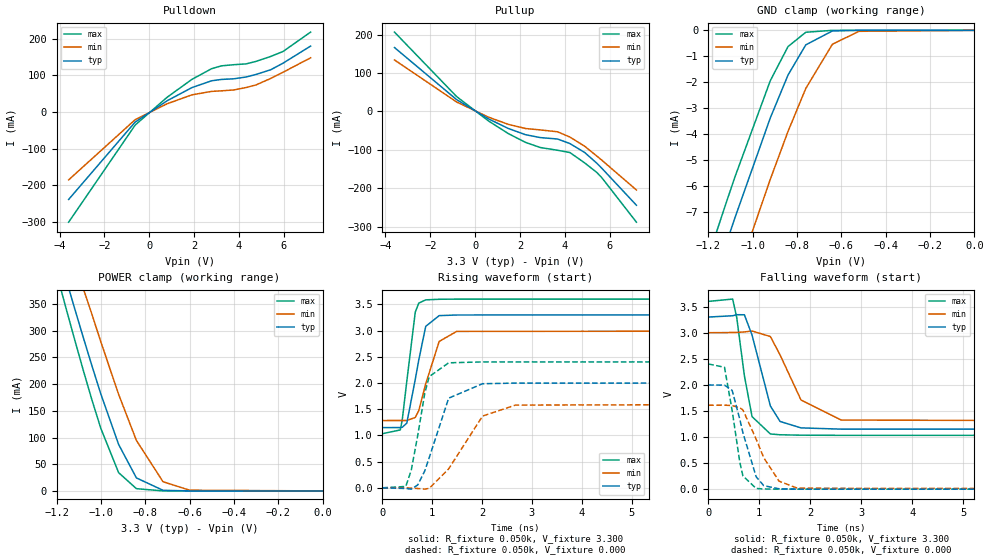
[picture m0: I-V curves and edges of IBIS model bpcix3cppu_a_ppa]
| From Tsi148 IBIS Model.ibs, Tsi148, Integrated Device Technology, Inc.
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|   MODEL bpcix3cppu_a_ppa
[Model]   bpcix3cppu_a_ppa
Model_type   I/O
Vinl  = 0.8V
Vinh  = 2.0V
Vref  = 0.0V
Rref  = 1k
Cref  = 10pF
Vmeas = 1.4V
| Values for delay from A to PAD (Tdo) are determined using
| Vref, Cref, Rref, and Vmeas.
|   INPUT TRANSITION ON DRIVER INPUT = 0.1ns
|   typ   min   max
| Tdo (rise)   1.34n   0.92n   2.02n
| Tdo (fall)   1.41n   1.01n   2.06n
|   INPUT TRANSITION ON DRIVER INPUT = 1.0ns
|   typ   min   max
| Tdo (rise)   1.37n   0.91n   2.08n
| Tdo (fall)   1.56n   1.16n   2.22n
|   typ   min   max
C_comp   2.58pF   2.53pF  2.63pF
[Temperature Range]   50.00   125.00   0.00
[Voltage Range]   3.300   3.000   3.600
|   typ   min   max
|[Supply]   VDD   1.80   1.65   1.95
|[Supply]   VDD330   3.30   3.00   3.60
[Add Submodel]
| Submodel Name   Mode
Up.bpcix3cppu_a.ppa   Non-Driving
Dn.bpcix3cppu_a.ppa   Non-Driving
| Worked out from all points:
|   slope of the pulldown table from 0 to 0.495 V, typ, clamps not added: 25.5 ohm
|   slope of the pullup table from 0 to 0.495 V, typ, clamps not added: 30.3 ohm
|   GND clamp passes 1 mA (typ) near -0.80 V on its own axis
|   POWER clamp passes 1 mA (typ) near -0.71 V on its own axis
|   rising waveform, R_fixture 0.050k, V_fixture 3.300: 20-80 % time 240ps typ, 295ps min, 185ps max; typ from 1.15 V to 3.3 V
|   falling waveform, R_fixture 0.050k, V_fixture 3.300: 20-80 % time 345ps typ, 534ps min, 232ps max; typ from 3.3 V to 1.15 V
|   rising waveform, R_fixture 0.050k, V_fixture 0.000: 20-80 % time 394ps typ, 626ps min, 264ps max; typ from 0 V to 2 V
|   falling waveform, R_fixture 0.050k, V_fixture 0.000: 20-80 % time 317ps typ, 434ps min, 221ps max; typ from 2 V to 0 V
[Pullup]   | Note: Vtable = Vcc - Vout
| Voltage   I(typ)   I(min)   I(max)
-3.6V     166.1mA    133.8mA    206.3mA
-830mV    30.72mA    24.48mA    38.72mA
600mV     -19.63mA   -15.18mA   -25.14mA
1.48V     -44.54mA   -33.84mA   -57.85mA
2.25V     -60.8mA    -44.7mA    -80.81mA
2.91V     -68.31mA   -48.31mA   -94.15mA
3.68V     -72mA      -53.25mA   -101.3mA
4.23V     -83.85mA   -66.9mA    -107.2mA
4.89V     -107.1mA   -90.82mA   -134.2mA
5.44V     -135.4mA   -116.7mA   -159.5mA
5.66V     -148.5mA   -127.4mA   -173.1mA
7.2V      -244.4mA   -204.7mA   -288.5mA
[Pulldown]   | Note: Vtable = Vout
| Voltage   I(typ)   I(min)   I(max)
-3.6V     -238.4mA   -185mA     -300.3mA
-630mV    -27.45mA   -20.86mA   -35.6mA
800mV     30.77mA    22.49mA    40.33mA
1.9V      66.46mA    46.73mA    88.87mA
2.78V     85.09mA    56.17mA    118mA
3.22V     88.75mA    57.7mA     125.8mA
3.77V     90.48mA    60.08mA    128.9mA
4.32V     95.42mA    66.66mA    131.1mA
4.76V     102.3mA    73.69mA    137.9mA
5.42V     115.2mA    91.42mA    151.4mA
5.97V     133.1mA    108.4mA    165mA
7.2V      179.7mA    147.7mA    217.8mA
[POWER_Clamp]   | Note: Vtable = Vcc - Vout
| Voltage   I(typ)   I(min)   I(max)
-3.6V     3.946A     3.816A     4.188A
-1.2V     455.7mA    530.2mA    407.9mA
-1.16V    400.6mA    479.4mA    346.3mA
-1.12V    343.9mA    429.2mA    285.8mA
-1.08V    288.1mA    379.7mA    226.7mA
-1.04V    233.7mA    330.1mA    169.8mA
-1V       181.1mA    278.8mA    116.7mA
-920mV    86.97mA    180.7mA    34.22mA
-840mV    24.39mA    94.6mA     4.235mA
-720mV    1.176mA    17.25mA    44uA
-600mV    19uA       1.348mA    0A
0V        0A         0A         0A
[GND_Clamp]   | Note: Vtable = Vout
| Voltage   I(typ)   I(min)   I(max)
-3.6V     -76.49mA   -78.79mA   -75.06mA
-1.28V    -12.45mA   -14.94mA   -10.87mA
-1.24V    -11.4mA    -13.88mA   -9.809mA
-1.2V     -10.35mA   -12.84mA   -8.759mA
-1.12V    -8.273mA   -10.76mA   -6.689mA
-1.08V    -7.253mA   -9.729mA   -5.675mA
-920mV    -3.381mA   -5.752mA   -1.944mA
-840mV    -1.725mA   -3.901mA   -626uA
-760mV    -561uA     -2.244mA   -74uA
-640mV    -23uA      -536uA     -1uA
-520mV    0A         -38uA      0A
0V        0A         0A         0A
[Ramp]
| variable   typ   min   max
  dV/dt_r   1.20/0.40n   0.97/0.64n   1.44/0.27n
  dV/dt_f   1.29/0.34n   1.03/0.53n   1.54/0.23n
R_load = 0.05k
[Rising Waveform]
R_fixture = 0.050k
V_fixture = 3.300
V_fixture_min = 3.000
V_fixture_max = 3.600
|   time   V(typ)   V(min)   V(max)
0s        1.148V     1.283V     1.032V
360ps     1.149V     1.284V     1.104V
400ps     1.155V     1.284V     1.302V
490ps     1.233V     1.284V     2.029V
660ps     2.066V     1.342V     3.35V
730ps     2.435V     1.47V      3.522V
870ps     3.08V      1.983V     3.585V
1.14ns    3.284V     2.792V     3.596V
1.49ns    3.296V     2.983V     3.599V
19.9ns    3.3V       3V         3.6V
[Falling Waveform]
R_fixture = 0.050k
V_fixture = 3.300
V_fixture_min = 3.000
V_fixture_max = 3.600
|   time   V(typ)   V(min)   V(max)
0s        3.3V       3V         3.6V
480ps     3.325V     3.004V     3.645V
560ps     3.345V     3.006V     3.289V
710ps     3.344V     3.014V     2.174V
860ps     2.954V     3.033V     1.391V
1.22ns    1.594V     2.926V     1.058V
1.41ns    1.298V     2.573V     1.043V
1.82ns    1.175V     1.71V      1.035V
2.61ns    1.151V     1.325V     1.032V
19.9ns    1.148V     1.283V     1.032V
[Rising Waveform]
R_fixture = 0.050k
V_fixture = 0.000
V_fixture_min = 0.000
V_fixture_max = 0.000
|   time   V(typ)   V(min)   V(max)
0s        0V         0V         0V
470ps     -13mV      -1mV       26mV
580ps     -26mV      -6mV       336mV
710ps     55mV       -14mV      1.002V
850ps     321mV      -25mV      1.802V
940ps     574mV      -10mV      2.121V
1.33ns    1.71V      361mV      2.384V
2.01ns    1.985V     1.368V     2.401V
2.67ns    1.997V     1.578V     2.401V
19.9ns    1.998V     1.609V     2.401V
[Falling Waveform]
R_fixture = 0.050k
V_fixture = 0.000
V_fixture_min = 0.000
V_fixture_max = 0.000
|   time   V(typ)   V(min)   V(max)
0s        1.998V     1.609V     2.401V
320ps     1.994V     1.611V     2.337V
470ps     1.894V     1.603V     1.506V
620ps     1.339V     1.56V      518mV
680ps     1.085V     1.52V      256mV
940ps     238mV      961mV      14mV
1.09ns    67mV       602mV      4mV
1.39ns    7mV        153mV      1mV
1.75ns    1mV        18mV       0V
19.9ns    0V         0V         0V
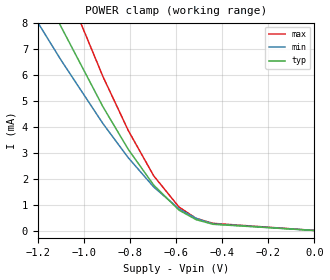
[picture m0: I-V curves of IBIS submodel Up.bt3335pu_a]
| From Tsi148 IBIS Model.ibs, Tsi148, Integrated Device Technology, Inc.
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[Submodel]  Up.bt3335pu_a
Submodel_type   Dynamic_clamp
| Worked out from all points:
|   POWER clamp passes 1 mA (typ) near -0.62 V on its own axis
[POWER Clamp]   | Note: Vtable = Vcc - Vout
| Voltage   I(typ)   I(min)   I(max)
-3.6V     60.61mA    47.86mA    76.15mA
-1.32V    11.99mA    9.826mA    15.04mA
-1.21V    9.903mA    8.182mA    12.41mA
-1.173V   9.222mA    7.646mA    11.55mA
-1.1V     7.889mA    6.594mA    9.87mA
-917mV    4.775mA    4.125mA    5.94mA
-807mV    3.129mA    2.806mA    3.856mA
-697mV    1.753mA    1.68mA     2.112mA
-587mV    784uA      834uA      902uA
-513mV    419uA      469uA      469uA
-440mV    240uA      257uA      277uA
0V        1uA        1uA        2uA
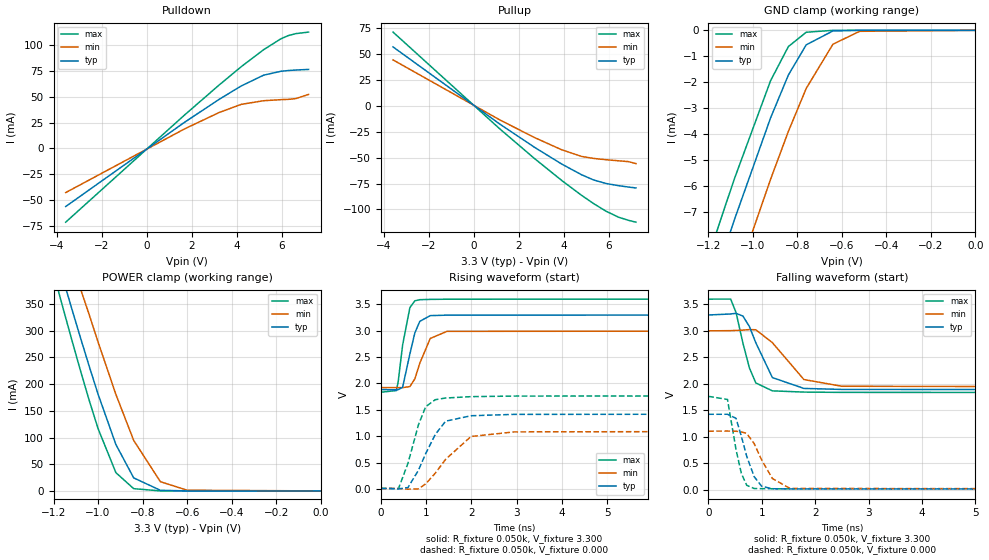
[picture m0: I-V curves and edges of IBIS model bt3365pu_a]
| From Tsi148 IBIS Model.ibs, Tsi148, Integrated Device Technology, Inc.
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|   MODEL bt3365pu_a
[Model]   bt3365pu_a
Model_type   I/O
Vinl  = 0.8V
Vinh  = 2.0V
Vref  = 0.0V
Rref  = 1k
Cref  = 10pF
Vmeas = 1.65V
| Values for delay from A to PAD (Tdo) are determined using
| Vref, Cref, Rref, and Vmeas.
|   INPUT TRANSITION ON DRIVER INPUT = 0.1ns
|   typ   min   max
| Tdo (rise)   1.60n   1.13n   2.30n
| Tdo (fall)   1.54n   1.16n   2.10n
|   INPUT TRANSITION ON DRIVER INPUT = 1.0ns
|   typ   min   max
| Tdo (rise)   1.81n   1.28n   2.56n
| Tdo (fall)   1.64n   1.27n   2.21n
|   typ   min   max
C_comp   1.08pF   1.01pF  1.15pF
[Temperature Range]   50.00   125.00   0.00
[Voltage Range]   3.300   3.000   3.600
|   typ   min   max
|[Supply]   VDD   1.80   1.65   1.95
|[Supply]   VDD330   3.30   3.00   3.60
[Add Submodel]
| Submodel Name   Mode
Up.bt3365pu_a   Non-Driving
Dn.bt3365pu_a   Non-Driving
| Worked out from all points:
|   slope of the pulldown table from 0 to 0.495 V, typ, clamps not added: 64.3 ohm
|   slope of the pullup table from 0 to 0.495 V, typ, clamps not added: 64.3 ohm
|   GND clamp passes 1 mA (typ) near -0.80 V on its own axis
|   POWER clamp passes 1 mA (typ) near -0.71 V on its own axis
|   rising waveform, R_fixture 0.050k, V_fixture 3.300: 20-80 % time 217ps typ, 266ps min, 173ps max; typ from 1.88 V to 3.3 V
|   falling waveform, R_fixture 0.050k, V_fixture 3.300: 20-80 % time 366ps typ, 512ps min, 264ps max; typ from 3.3 V to 1.88 V
|   rising waveform, R_fixture 0.050k, V_fixture 0.000: 20-80 % time 486ps typ, 653ps min, 352ps max; typ from 0.011 V to 1.42 V
|   falling waveform, R_fixture 0.050k, V_fixture 0.000: 20-80 % time 249ps typ, 334ps min, 183ps max; typ from 1.42 V to 0.011 V
[Pullup]   | Note: Vtable = Vcc - Vout
| Voltage   I(typ)   I(min)   I(max)
-3.6V     56.82mA    44.29mA    71.12mA
1.15V     -17.69mA   -13.64mA   -22.34mA
2.69V     -40.04mA   -30.64mA   -50.87mA
3.9V      -56.2mA    -42.43mA   -72.02mA
4.78V     -66.5mA    -48.84mA   -86.33mA
5.33V     -71.66mA   -50.81mA   -94.53mA
5.88V     -74.99mA   -52.04mA   -101.8mA
6.43V     -77.06mA   -53.07mA   -107.5mA
6.87V     -78.39mA   -53.87mA   -110.5mA
7.2V      -79.27mA   -55.73mA   -112.3mA
[Pulldown]   | Note: Vtable = Vout
| Voltage   I(typ)   I(min)   I(max)
-3.6V     -56.45mA   -42.91mA   -71.65mA
1.68V     25.31mA    18.91mA    32.36mA
3.22V     47.63mA    34.86mA    61.54mA
4.21V     60.73mA    42.82mA    79.46mA
5.2V      71.14mA    46.34mA    95.89mA
5.97V     74.94mA    47.37mA    106.5mA
6.3V      75.66mA    47.67mA    109.6mA
6.63V     76.15mA    48.37mA    111.5mA
7.2V      76.74mA    52.47mA    113mA
[POWER_Clamp]   | Note: Vtable = Vcc - Vout
| Voltage   I(typ)   I(min)   I(max)
-3.6V     3.946A     3.816A     4.188A
-1.2V     455.7mA    530.2mA    407.9mA
-1.16V    400.6mA    479.4mA    346.3mA
-1.12V    343.9mA    429.2mA    285.8mA
-1.08V    288.1mA    379.7mA    226.7mA
-1.04V    233.7mA    330.1mA    169.8mA
-1V       181.1mA    278.8mA    116.7mA
-920mV    86.97mA    180.7mA    34.22mA
-840mV    24.39mA    94.6mA     4.235mA
-720mV    1.176mA    17.25mA    44uA
-600mV    19uA       1.348mA    0A
0V        0A         0A         0A
[GND_Clamp]   | Note: Vtable = Vout
| Voltage   I(typ)   I(min)   I(max)
-3.6V     -76.49mA   -78.79mA   -75.06mA
-1.28V    -12.45mA   -14.94mA   -10.87mA
-1.24V    -11.4mA    -13.88mA   -9.809mA
-1.2V     -10.35mA   -12.84mA   -8.759mA
-1.12V    -8.273mA   -10.76mA   -6.689mA
-1.08V    -7.253mA   -9.729mA   -5.675mA
-920mV    -3.381mA   -5.752mA   -1.944mA
-840mV    -1.725mA   -3.901mA   -626uA
-760mV    -561uA     -2.244mA   -74uA
-640mV    -23uA      -536uA     -1uA
-520mV    0A         -38uA      0A
0V        0A         0A         0A
[Ramp]
| variable   typ   min   max
  dV/dt_r   0.85/0.49n   0.66/0.65n   1.05/0.35n
  dV/dt_f   0.85/0.37n   0.65/0.51n   1.06/0.26n
R_load = 0.050k
[Rising Waveform]
R_fixture = 0.050k
V_fixture = 3.300
V_fixture_min = 3.000
V_fixture_max = 3.600
|   time   V(typ)   V(min)   V(max)
0s        1.883V     1.922V     1.834V
340ps     1.88V      1.922V     1.865V
380ps     1.881V     1.922V     2.018V
480ps     1.927V     1.921V     2.729V
640ps     2.559V     1.941V     3.437V
750ps     2.959V     2.087V     3.567V
860ps     3.178V     2.386V     3.588V
1.09ns    3.286V     2.853V     3.594V
1.46ns    3.295V     2.988V     3.597V
19.9ns    3.3V       3V         3.6V
[Falling Waveform]
R_fixture = 0.050k
V_fixture = 3.300
V_fixture_min = 3.000
V_fixture_max = 3.600
|   time   V(typ)   V(min)   V(max)
0s        3.3V       3V         3.6V
420ps     3.319V     3.004V     3.601V
520ps     3.332V     3.008V     3.348V
650ps     3.279V     3.014V     2.765V
770ps     3.082V     3.024V     2.301V
890ps     2.776V     3.021V     2.016V
1.2ns     2.117V     2.777V     1.866V
1.79ns    1.912V     2.08V      1.843V
2.5ns     1.893V     1.953V     1.837V
19.9ns    1.883V     1.922V     1.834V
[Rising Waveform]
R_fixture = 0.050k
V_fixture = 0.000
V_fixture_min = 0.000
V_fixture_max = 0.000
|   time   V(typ)   V(min)   V(max)
0s        11mV       8mV        14mV
390ps     0V         8mV        9mV
600ps     28mV       -4mV       492mV
830ps     356mV      2mV        1.218V
990ps     670mV      97mV       1.56V
1.2ns     1.032V     298mV      1.692V
1.43ns    1.285V     562mV      1.724V
1.99ns    1.388V     995mV      1.75V
2.95ns    1.414V     1.082V     1.761V
19.9ns    1.423V     1.104V     1.763V
[Falling Waveform]
R_fixture = 0.050k
V_fixture = 0.000
V_fixture_min = 0.000
V_fixture_max = 0.000
|   time   V(typ)   V(min)   V(max)
0s        1.423V     1.104V     1.763V
360ps     1.424V     1.106V     1.704V
520ps     1.347V     1.103V     756mV
620ps     1.007V     1.091V     304mV
720ps     629mV      1.061V     81mV
860ps     244mV      869mV      20mV
1ns       62mV       559mV      17mV
1.2ns     16mV       210mV      16mV
1.53ns    13mV       21mV       15mV
19.9ns    11mV       8mV        14mV
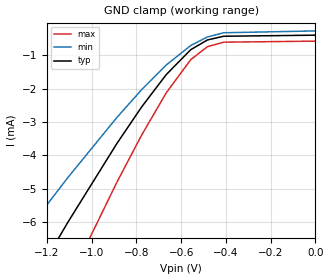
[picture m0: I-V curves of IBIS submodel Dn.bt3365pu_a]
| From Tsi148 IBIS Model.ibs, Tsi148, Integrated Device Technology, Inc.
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[Submodel]  Dn.bt3365pu_a
Submodel_type   Dynamic_clamp
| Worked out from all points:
|   GND clamp passes 1 mA (typ) near -0.59 V on its own axis
[GND Clamp]   | Note: Vtable =  Vout
| Voltage   I(typ)   I(min)   I(max)
-3.6V     -37.12mA   -28.73mA   -46.73mA
-1.51V    -10.7mA    -8.257mA   -13.76mA
-1.29V    -8.101mA   -6.267mA   -10.48mA
-1.143V   -6.422mA   -4.982mA   -8.352mA
-1.107V   -6.01mA    -4.668mA   -7.829mA
-887mV    -3.638mA   -2.858mA   -4.799mA
-777mV    -2.548mA   -2.029mA   -3.393mA
-667mV    -1.576mA   -1.288mA   -2.124mA
-557mV    -826uA     -701uA     -1.125mA
-483mV    -536uA     -447uA     -738uA
-410mV    -424uA     -320uA     -602uA
0V        -392uA     -264uA     -571uA
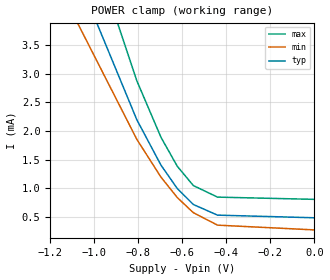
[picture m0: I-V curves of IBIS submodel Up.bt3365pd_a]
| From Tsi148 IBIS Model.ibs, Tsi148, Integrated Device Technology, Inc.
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[Submodel]  Up.bt3365pd_a
Submodel_type   Dynamic_clamp
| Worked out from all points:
|   POWER clamp passes 1 mA (typ) near -0.62 V on its own axis
[POWER Clamp]   | Note: Vtable = Vcc - Vout
| Voltage   I(typ)   I(min)   I(max)
-3.6V     34.94mA    28.15mA    43.2mA
-1.393V   8.069mA    6.605mA    10.14mA
-1.357V   7.662mA    6.277mA    9.637mA
-1.247V   6.463mA    5.311mA    8.158mA
-1.137V   5.302mA    4.374mA    6.725mA
-1.1V     4.925mA    4.069mA    6.259mA
-807mV    2.2mA      1.857mA    2.882mA
-697mV    1.404mA    1.194mA    1.891mA
-623mV    996uA      838uA      1.385mA
-550mV    716uA      573uA      1.047mA
-440mV    530uA      355uA      845uA
0V        484uA      272uA      806uA
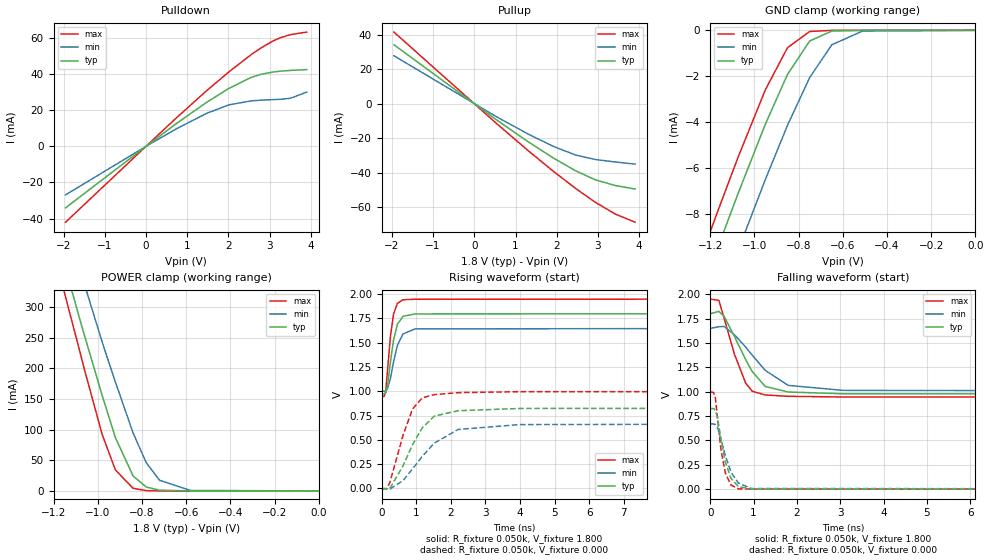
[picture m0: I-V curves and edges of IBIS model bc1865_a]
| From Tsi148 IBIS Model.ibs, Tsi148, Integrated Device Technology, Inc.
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|   MODEL bc1865_a
[Model]   bc1865_a
Model_type   I/O
Vinl  = 0.63V
Vinh  = 1.17V
Vref  = 0.0V
Rref  = 1k
Cref  = 10pF
Vmeas = 0.9V
| Values for delay from A to PAD (Tdo) are determined using
| Vref, Cref, Rref, and Vmeas.
|   INPUT TRANSITION ON DRIVER INPUT = 0.1ns
|   typ   min   max
| Tdo (rise)   1.42n   1.01n   1.99n
| Tdo (fall)   1.31n   1.01n   1.69n
|   INPUT TRANSITION ON DRIVER INPUT = 1.0ns
|   typ   min   max
| Tdo (rise)   1.49n   1.09n   2.07n
| Tdo (fall)   1.38n   1.11n   1.76n
|   typ   min   max
C_comp   1.31pF   1.26pF  1.35pF
[Temperature Range]   50.00   125.00   0.00
[Voltage Range]   1.800   1.650   1.950
|   typ   min   max
|[Supply]   VDD   1.80   1.65   1.95
[Add Submodel]
| Submodel Name   Mode
Up.bc1865_a   Non-Driving
Dn.bc1865_a   Non-Driving
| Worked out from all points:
|   slope of the pulldown table from 0 to 0.27 V, typ, clamps not added: 57.5 ohm
|   slope of the pullup table from 0 to 0.27 V, typ, clamps not added: 57.6 ohm
|   GND clamp passes 1 mA (typ) near -0.80 V on its own axis
|   POWER clamp passes 1 mA (typ) near -0.71 V on its own axis
|   rising waveform, R_fixture 0.050k, V_fixture 1.800: 20-80 % time 207ps typ, 249ps min, 165ps max; typ from 0.974 V to 1.8 V
|   falling waveform, R_fixture 0.050k, V_fixture 1.800: 20-80 % time 592ps typ, 803ps min, 428ps max; typ from 1.8 V to 0.974 V
|   rising waveform, R_fixture 0.050k, V_fixture 0.000: 20-80 % time 731ps typ, 1.02ns min, 506ps max; typ from 0 V to 0.828 V
|   falling waveform, R_fixture 0.050k, V_fixture 0.000: 20-80 % time 229ps typ, 288ps min, 175ps max; typ from 0.828 V to 0 V
[Pullup]   | Note: Vtable = Vcc - Vout
| Voltage   I(typ)   I(min)   I(max)
-1.95V    34.37mA    27.99mA    41.74mA
540mV     -9.309mA   -7.483mA   -11.41mA
1.32V     -22.21mA   -17.69mA   -27.42mA
1.92V     -31.46mA   -24.72mA   -39.2mA
2.46V     -38.9mA    -29.74mA   -49.17mA
2.94V     -44.15mA   -32.33mA   -57.24mA
3.42V     -47.44mA   -33.76mA   -64.01mA
3.9V      -49.45mA   -34.99mA   -68.75mA
[Pulldown]   | Note: Vtable = Vout
| Voltage   I(typ)   I(min)   I(max)
-1.95V    -34.04mA   -26.86mA   -42.01mA
90mV      1.574mA    1.228mA    1.953mA
750mV     12.84mA    9.891mA    16.04mA
1.47V     24.37mA    18.27mA    30.8mA
2.01V     32.1mA     23mA       41.25mA
2.55V     38.21mA    25.2mA     50.79mA
2.79V     39.96mA    25.6mA     54.54mA
3.09V     41.23mA    25.93mA    58.49mA
3.27V     41.69mA    26.09mA    60.29mA
3.51V     42.1mA     26.69mA    61.94mA
3.9V      42.56mA    30.08mA    63.33mA
[POWER_Clamp]   | Note: Vtable = Vcc - Vout
| Voltage   I(typ)   I(min)   I(max)
-1.95V    1.502A     1.515A     1.547A
-1.18V    409.4mA    486.3mA    365.4mA
-1.14V    356.3mA    435.8mA    308.7mA
-1.08V    278.9mA    361.4mA    226.2mA
-1.06V    253.8mA    337.1mA    197.9mA
-980mV    155.9mA    243.1mA    92.22mA
-920mV    86.96mA    177.7mA    34.21mA
-840mV    24.37mA    94.58mA    4.222mA
-780mV    6.248mA    45.82mA    508uA
-720mV    1.17mA     17.24mA    43uA
-580mV    9uA        802uA      0A
0V        0A         0A         0A
[GND_Clamp]   | Note: Vtable = Vout
| Voltage   I(typ)   I(min)   I(max)
-1.95V    -30.64mA   -33.06mA   -29.11mA
-1.25V    -11.66mA   -14.15mA   -10.07mA
-1.23V    -11.13mA   -13.62mA   -9.546mA
-1.17V    -9.565mA   -12.05mA   -7.977mA
-1.09V    -7.506mA   -9.985mA   -5.927mA
-1.07V    -7mA       -9.474mA   -5.425mA
-950mV    -4.069mA   -6.476mA   -2.576mA
-850mV    -1.912mA   -4.124mA   -751uA
-750mV    -465uA     -2.058mA   -52uA
-650mV    -32uA      -629uA     -1uA
-510mV    0A         -29uA      0A
0V        0A         0A         0A
[Ramp]
| variable   typ   min   max
  dV/dt_r   0.50/0.73n   0.40/1.01n   0.60/0.51n
  dV/dt_f   0.50/0.59n   0.39/0.80n   0.60/0.43n
R_load = 0.050k
[Rising Waveform]
R_fixture = 0.050k
V_fixture = 1.800
V_fixture_min = 1.650
V_fixture_max = 1.950
|   time   V(typ)   V(min)   V(max)
0s        974mV      1.001V     944mV
70ps      974mV      1.001V     949mV
110ps     985mV      1.004V     994mV
160ps     1.05V      1.022V     1.196V
250ps     1.307V     1.136V     1.572V
340ps     1.532V     1.307V     1.797V
450ps     1.69V      1.473V     1.906V
610ps     1.772V     1.59V      1.943V
960ps     1.797V     1.643V     1.948V
19.9ns    1.8V       1.65V      1.95V
[Falling Waveform]
R_fixture = 0.050k
V_fixture = 1.800
V_fixture_min = 1.650
V_fixture_max = 1.950
|   time   V(typ)   V(min)   V(max)
0s        1.8V       1.65V      1.951V
200ps     1.825V     1.667V     1.937V
320ps     1.774V     1.67V      1.757V
560ps     1.568V     1.585V     1.384V
820ps     1.328V     1.458V     1.087V
970ps     1.207V     1.375V     1.005V
1.27ns    1.054V     1.219V     967mV
1.8ns     997mV      1.065V     953mV
3.06ns    979mV      1.014V     946mV
19.9ns    974mV      1.001V     945mV
[Rising Waveform]
R_fixture = 0.050k
V_fixture = 0.000
V_fixture_min = 0.000
V_fixture_max = 0.000
|   time   V(typ)   V(min)   V(max)
0s        0V         0V         -1mV
140ps     -8mV       -6mV       -3mV
230ps     0V         -8mV       57mV
610ps     230mV      80mV       544mV
890ps     451mV      201mV      819mV
1.17ns    624mV      330mV      933mV
1.52ns    745mV      467mV      966mV
2.21ns    800mV      607mV      986mV
3.98ns    823mV      657mV      996mV
19.9ns    828mV      669mV      998mV
[Falling Waveform]
R_fixture = 0.050k
V_fixture = 0.000
V_fixture_min = 0.000
V_fixture_max = 0.000
|   time   V(typ)   V(min)   V(max)
0s        828mV      669mV      999mV
80ps      827mV      669mV      991mV
120ps     809mV      662mV      937mV
170ps     731mV      632mV      723mV
250ps     509mV      512mV      400mV
350ps     278mV      344mV      166mV
480ps     111mV      174mV      42mV
650ps     27mV       63mV       3mV
950ps     1mV        7mV        1mV
19.9ns    0V         0V         0V
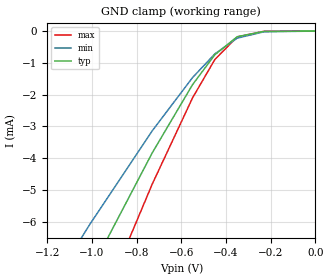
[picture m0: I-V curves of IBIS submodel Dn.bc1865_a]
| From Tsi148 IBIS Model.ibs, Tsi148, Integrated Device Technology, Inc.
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[Submodel]  Dn.bc1865_a
Submodel_type   Dynamic_clamp
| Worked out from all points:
|   GND clamp passes 1 mA (typ) near -0.48 V on its own axis
[GND Clamp]   | Note: Vtable =  Vout
| Voltage   I(typ)   I(min)   I(max)
-1.95V    -21.23mA   -16.93mA   -26.21mA
-1.43V    -13.58mA   -10.83mA   -16.87mA
-1.01V    -7.593mA   -6.089mA   -9.495mA
-730mV    -3.831mA   -3.137mA   -4.814mA
-550mV    -1.688mA   -1.465mA   -2.105mA
-450mV    -744uA     -717uA     -894uA
-350mV    -177uA     -222uA     -183uA
-230mV    -10uA      -22uA      -6uA
0V        0A         0A         0A
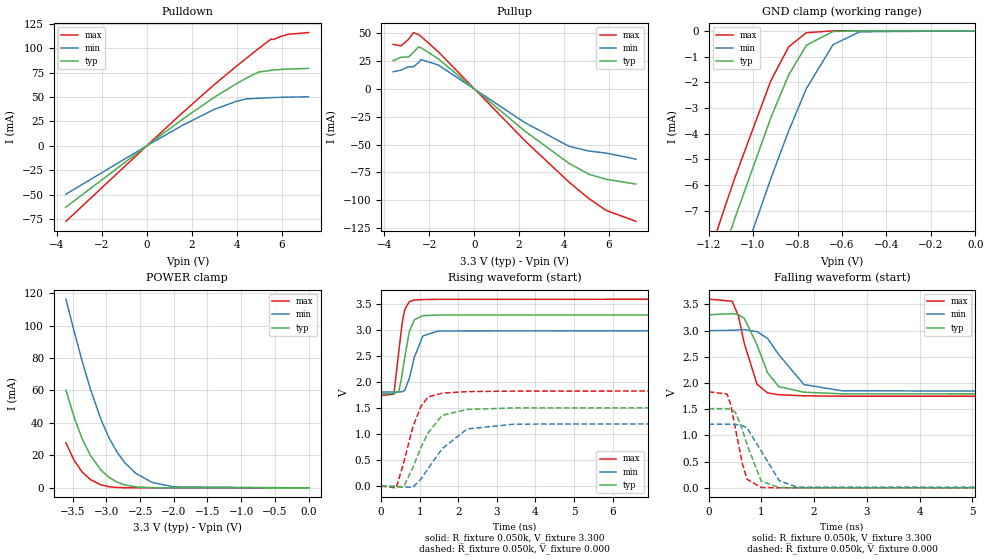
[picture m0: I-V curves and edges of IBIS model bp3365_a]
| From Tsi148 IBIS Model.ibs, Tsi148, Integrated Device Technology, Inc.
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|   MODEL bp3365_a
[Model]   bp3365_a
Model_type   I/O
Vinl  = 0.8V
Vinh  = 2.0V
Vref  = 0.0V
Rref  = 1k
Cref  = 10pF
Vmeas = 1.65V
| Values for delay from A to PAD (Tdo) are determined using
| Vref, Cref, Rref, and Vmeas.
|   INPUT TRANSITION ON DRIVER INPUT = 0.1ns
|   typ   min   max
| Tdo (rise)   1.62n   1.15n   2.28n
| Tdo (fall)   1.50n   1.16n   1.98n
|   INPUT TRANSITION ON DRIVER INPUT = 1.0ns
|   typ   min   max
| Tdo (rise)   1.82n   1.30n   2.54n
| Tdo (fall)   1.61n   1.26n   2.10n
|   typ   min   max
C_comp   1.05pF   1.03pF  1.07pF
[Temperature Range]   50.00   125.00   0.00
[Voltage Range]   3.300   3.000   3.600
|   typ   min   max
|[Supply]   VDD   1.80   1.65   1.95
|[Supply]   VDD330   3.30   3.00   3.60
[Add Submodel]
| Submodel Name   Mode
Up.bp3365_a   Non-Driving
Dn.bp3365_a   Non-Driving
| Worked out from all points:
|   slope of the pulldown table from 0 to 0.495 V, typ, clamps not added: 57.3 ohm
|   slope of the pullup table from 0 to 0.495 V, typ, clamps not added: 58 ohm
|   GND clamp passes 1 mA (typ) near -0.80 V on its own axis
|   POWER clamp passes 1 mA (typ) near -2.63 V on its own axis
|   rising waveform, R_fixture 0.050k, V_fixture 3.300: 20-80 % time 209ps typ, 254ps min, 170ps max; typ from 1.78 V to 3.3 V
|   falling waveform, R_fixture 0.050k, V_fixture 3.300: 20-80 % time 362ps typ, 500ps min, 267ps max; typ from 3.3 V to 1.78 V
|   rising waveform, R_fixture 0.050k, V_fixture 0.000: 20-80 % time 593ps typ, 798ps min, 430ps max; typ from 0 V to 1.51 V
|   falling waveform, R_fixture 0.050k, V_fixture 0.000: 20-80 % time 296ps typ, 408ps min, 216ps max; typ from 1.51 V to 0 V
[Pullup]   | Note: Vtable = Vcc - Vout
| Voltage   I(typ)   I(min)   I(max)
-3.6V     25.45mA    15.41mA    39.92mA
-3.25V    28.46mA    16.85mA    38.66mA
-2.92V    28.68mA    19.94mA    44.55mA
-2.7V     32.79mA    19.89mA    50.56mA
-2.48V    37.73mA    23.59mA    48.68mA
-2.37V    37.05mA    26.29mA    47.22mA
-1.6V     27.02mA    21.49mA    33.37mA
2.25V     -37.73mA   -30.18mA   -46.33mA
4.23V     -66.91mA   -51.56mA   -83.84mA
5.11V     -76.6mA    -55.74mA   -98.5mA
5.88V     -81.11mA   -57.63mA   -109.1mA
7.2V      -85.42mA   -63.05mA   -118.8mA
[Pulldown]   | Note: Vtable = Vout
| Voltage   I(typ)   I(min)   I(max)
-3.6V     -62.76mA   -49.52mA   -77.34mA
250mV     4.379mA    3.419mA    5.424mA
1.57V     26.9mA     20.75mA    33.53mA
3V        49.67mA    37.27mA    62.65mA
3.99V     63.66mA    45.62mA    81.56mA
4.43V     69.36mA    48.06mA    89.54mA
4.98V     75.61mA    48.71mA    99.72mA
5.53V     77.3mA     49.34mA    109.3mA
5.64V     77.6mA     49.44mA    108.9mA
5.97V     78.25mA    49.67mA    112.2mA
6.3V      78.66mA    49.86mA    114.2mA
7.2V      79.29mA    50.22mA    116mA
[POWER_Clamp]   | Note: Vtable = Vcc - Vout
| Voltage   I(typ)   I(min)   I(max)
-3.6V     60.2mA     116.3mA    27.69mA
-3.48V    43.67mA    96.64mA    17.04mA
-3.36V    30.3mA     78.14mA    9.798mA
-3.24V    20.18mA    61.24mA    5.162mA
-3.08V    10.92mA    42.12mA    1.825mA
-2.96V    6.444mA    30.76mA    703uA
-2.84V    3.523mA    21.89mA    233uA
-2.72V    1.75mA     15.16mA    70uA
-2.56V    578uA      8.808mA    13uA
-2.32V    80uA       3.344mA    1uA
-2V       5uA        606uA      0A
0V        0A         0A         0A
[GND_Clamp]   | Note: Vtable = Vout
| Voltage   I(typ)   I(min)   I(max)
-3.6V     -76.49mA   -78.79mA   -75.06mA
-1.28V    -12.45mA   -14.94mA   -10.87mA
-1.24V    -11.4mA    -13.88mA   -9.809mA
-1.2V     -10.35mA   -12.84mA   -8.759mA
-1.12V    -8.273mA   -10.76mA   -6.689mA
-1.08V    -7.253mA   -9.729mA   -5.675mA
-920mV    -3.381mA   -5.752mA   -1.944mA
-840mV    -1.725mA   -3.901mA   -626uA
-760mV    -561uA     -2.244mA   -74uA
-640mV    -23uA      -536uA     -1uA
-520mV    0A         -38uA      0A
0V        0A         0A         0A
[Ramp]
| variable   typ   min   max
  dV/dt_r   0.91/0.59n   0.73/0.80n   1.10/0.43n
  dV/dt_f   0.91/0.36n   0.71/0.50n   1.11/0.27n
R_load = 0.050k
[Rising Waveform]
R_fixture = 0.050k
V_fixture = 3.300
V_fixture_min = 3.000
V_fixture_max = 3.600
|   time   V(typ)   V(min)   V(max)
0s        1.781V     1.812V     1.743V
330ps     1.778V     1.812V     1.773V
460ps     1.832V     1.812V     2.617V
540ps     2.137V     1.817V     3.12V
610ps     2.475V     1.841V     3.396V
730ps     2.974V     2.076V     3.552V
860ps     3.203V     2.478V     3.584V
1.08ns    3.281V     2.89V      3.592V
1.48ns    3.294V     2.987V     3.596V
19.9ns    3.3V       3V         3.6V
[Falling Waveform]
R_fixture = 0.050k
V_fixture = 3.300
V_fixture_min = 3.000
V_fixture_max = 3.600
|   time   V(typ)   V(min)   V(max)
0s        3.3V       3V         3.6V
450ps     3.324V     3.006V     3.56V
570ps     3.304V     3.012V     3.266V
680ps     3.231V     3.019V     2.746V
920ps     2.726V     2.98V      1.975V
1.12ns    2.196V     2.85V      1.813V
1.33ns    1.932V     2.543V     1.777V
1.81ns    1.824V     1.97V      1.756V
2.53ns    1.794V     1.852V     1.748V
19.9ns    1.781V     1.812V     1.743V
[Rising Waveform]
R_fixture = 0.050k
V_fixture = 0.000
V_fixture_min = 0.000
V_fixture_max = 0.000
|   time   V(typ)   V(min)   V(max)
0s        0V         0V         0V
390ps     -15mV      -1mV       -33mV
580ps     -17mV      -16mV      440mV
820ps     355mV      -23mV      1.135V
1.03ns    745mV      135mV      1.535V
1.22ns    1.028V     344mV      1.718V
1.58ns    1.363V     721mV      1.79V
2.23ns    1.476V     1.101V     1.82V
3.46ns    1.506V     1.194V     1.83V
19.9ns    1.512V     1.213V     1.832V
[Falling Waveform]
R_fixture = 0.050k
V_fixture = 0.000
V_fixture_min = 0.000
V_fixture_max = 0.000
|   time   V(typ)   V(min)   V(max)
0s        1.512V     1.213V     1.832V
350ps     1.512V     1.215V     1.79V
420ps     1.5V       1.214V     1.595V
510ps     1.442V     1.209V     1.127V
640ps     1.113V     1.187V     467mV
730ps     824mV      1.144V     163mV
1ns       124mV      701mV      8mV
1.34ns    7mV        139mV      1mV
1.68ns    1mV        13mV       1mV
19.9ns    0V         0V         0V
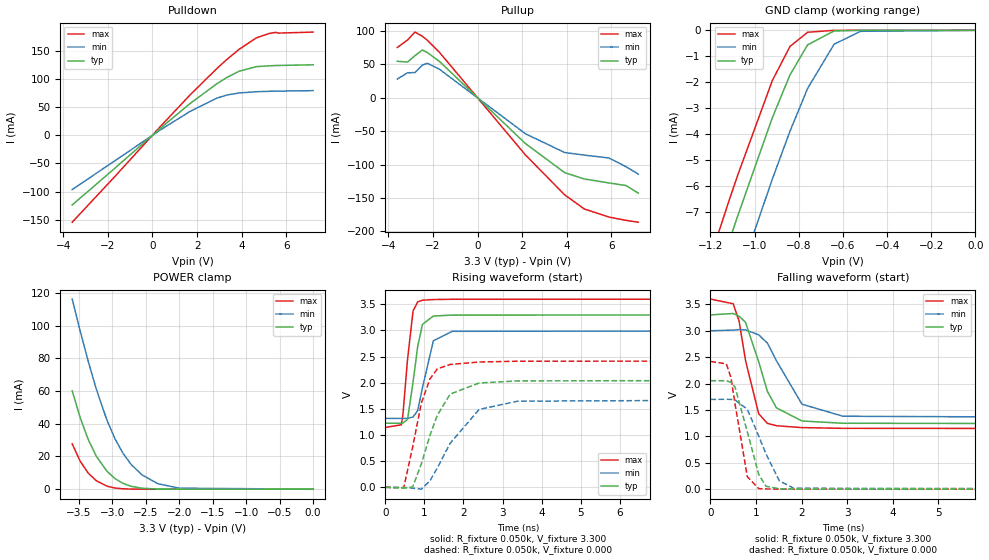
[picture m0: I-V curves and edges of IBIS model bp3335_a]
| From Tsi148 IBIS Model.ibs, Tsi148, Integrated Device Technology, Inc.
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|   MODEL bp3335_a
[Model]   bp3335_a
Model_type   I/O
Vinl  = 0.8V
Vinh  = 2.0V
Vref  = 0.0V
Rref  = 1k
Cref  = 10pF
Vmeas = 1.65V
| Values for delay from A to PAD (Tdo) are determined using
| Vref, Cref, Rref, and Vmeas.
|   INPUT TRANSITION ON DRIVER INPUT = 0.1ns
|   typ   min   max
| Tdo (rise)   1.53n   1.08n   2.18n
| Tdo (fall)   1.42n   1.07n   1.91n
|   INPUT TRANSITION ON DRIVER INPUT = 1.0ns
|   typ   min   max
| Tdo (rise)   1.73n   1.22n   2.43n
| Tdo (fall)   1.53n   1.18n   2.03n
|   typ   min   max
C_comp   1.44pF   1.40pF  1.49pF
[Temperature Range]   50.00   125.00   0.00
[Voltage Range]   3.300   3.000   3.600
|   typ   min   max
|[Supply]   VDD   1.80   1.65   1.95
|[Supply]   VDD330   3.30   3.00   3.60
[Add Submodel]
| Submodel Name   Mode
Up.bp3335_a   Non-Driving
Dn.bp3335_a   Non-Driving
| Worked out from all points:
|   slope of the pulldown table from 0 to 0.495 V, typ, clamps not added: 29 ohm
|   slope of the pullup table from 0 to 0.495 V, typ, clamps not added: 29.8 ohm
|   GND clamp passes 1 mA (typ) near -0.80 V on its own axis
|   POWER clamp passes 1 mA (typ) near -2.63 V on its own axis
|   rising waveform, R_fixture 0.050k, V_fixture 3.300: 20-80 % time 221ps typ, 271ps min, 175ps max; typ from 1.23 V to 3.3 V
|   falling waveform, R_fixture 0.050k, V_fixture 3.300: 20-80 % time 452ps typ, 631ps min, 323ps max; typ from 3.3 V to 1.23 V
|   rising waveform, R_fixture 0.050k, V_fixture 0.000: 20-80 % time 617ps typ, 868ps min, 431ps max; typ from 0 V to 2.05 V
|   falling waveform, R_fixture 0.050k, V_fixture 0.000: 20-80 % time 359ps typ, 507ps min, 256ps max; typ from 2.05 V to 0 V
[Pullup]   | Note: Vtable = Vcc - Vout
| Voltage   I(typ)   I(min)   I(max)
-3.6V     54.43mA    27.88mA    75.01mA
-3.14V    53.24mA    37.21mA    86.38mA
-2.81V    62.81mA    37.51mA    98.03mA
-2.48V    71.25mA    48.66mA    91.83mA
-2.26V    67.47mA    51.43mA    85.93mA
-1.71V    54.18mA    42.46mA    67.72mA
2.14V     -68.48mA   -53.88mA   -85.47mA
3.9V      -112mA     -81.97mA   -145.2mA
4.78V     -121.5mA   -85.81mA   -166.3mA
5.88V     -127.4mA   -90.11mA   -178.4mA
6.65V     -131.3mA   -103.1mA   -183.4mA
7.2V      -142.6mA   -114.2mA   -186.1mA
[Pulldown]   | Note: Vtable = Vout
| Voltage   I(typ)   I(min)   I(max)
-3.6V     -123.7mA   -96.37mA   -154.3mA
-1.73V    -60.06mA   -46.57mA   -75.12mA
360mV     12.47mA    9.553mA    15.69mA
1.68V     56.04mA    42.08mA    71.27mA
2.89V     91.41mA    65.77mA    118.4mA
3.33V     102.4mA    71.27mA    134.2mA
3.88V     113.4mA    74.9mA     152.2mA
4.65V     121.6mA    77.1mA     172.5mA
5.2V      123mA      77.82mA    180.1mA
5.53V     123.6mA    78.13mA    182.5mA
5.64V     123.7mA    78.21mA    181.1mA
7.2V      124.9mA    79.05mA    182.9mA
[POWER_Clamp]   | Note: Vtable = Vcc - Vout
| Voltage   I(typ)   I(min)   I(max)
-3.6V     60.2mA     116.3mA    27.69mA
-3.48V    43.67mA    96.64mA    17.04mA
-3.36V    30.3mA     78.14mA    9.798mA
-3.24V    20.18mA    61.24mA    5.162mA
-3.08V    10.92mA    42.12mA    1.825mA
-2.96V    6.444mA    30.76mA    703uA
-2.84V    3.523mA    21.89mA    233uA
-2.72V    1.75mA     15.16mA    70uA
-2.56V    578uA      8.808mA    13uA
-2.32V    80uA       3.344mA    1uA
-2V       5uA        606uA      0A
0V        0A         0A         0A
[GND_Clamp]   | Note: Vtable = Vout
| Voltage   I(typ)   I(min)   I(max)
-3.6V     -76.49mA   -78.79mA   -75.06mA
-1.28V    -12.45mA   -14.94mA   -10.87mA
-1.24V    -11.4mA    -13.88mA   -9.809mA
-1.2V     -10.35mA   -12.84mA   -8.759mA
-1.12V    -8.273mA   -10.76mA   -6.689mA
-1.08V    -7.253mA   -9.729mA   -5.675mA
-920mV    -3.381mA   -5.752mA   -1.944mA
-840mV    -1.725mA   -3.901mA   -626uA
-760mV    -561uA     -2.244mA   -74uA
-640mV    -23uA      -536uA     -1uA
-520mV    0A         -38uA      0A
0V        0A         0A         0A
[Ramp]
| variable   typ   min   max
  dV/dt_r   1.23/0.62n   1.02/0.87n   1.45/0.43n
  dV/dt_f   1.24/0.45n   1.01/0.63n   1.47/0.32n
R_load = 0.050k
[Rising Waveform]
R_fixture = 0.050k
V_fixture = 3.300
V_fixture_min = 3.000
V_fixture_max = 3.600
|   time   V(typ)   V(min)   V(max)
0s        1.226V     1.318V     1.144V
410ps     1.224V     1.317V     1.195V
450ps     1.227V     1.317V     1.381V
570ps     1.3V       1.319V     2.454V
710ps     2.013V     1.343V     3.373V
830ps     2.698V     1.471V     3.547V
950ps     3.115V     1.902V     3.578V
1.23ns    3.276V     2.803V     3.591V
1.71ns    3.293V     2.983V     3.596V
19.9ns    3.3V       3V         3.6V
[Falling Waveform]
R_fixture = 0.050k
V_fixture = 3.300
V_fixture_min = 3.000
V_fixture_max = 3.600
|   time   V(typ)   V(min)   V(max)
0s        3.3V       3V         3.6V
500ps     3.327V     3.012V     3.511V
630ps     3.275V     3.021V     3.179V
770ps     3.16V      3.016V     2.437V
1.06ns    2.412V     2.922V     1.428V
1.25ns    1.853V     2.767V     1.246V
1.45ns    1.539V     2.431V     1.201V
2.01ns    1.291V     1.609V     1.166V
2.91ns    1.248V     1.381V     1.152V
19.9ns    1.226V     1.318V     1.144V
[Rising Waveform]
R_fixture = 0.050k
V_fixture = 0.000
V_fixture_min = 0.000
V_fixture_max = 0.000
|   time   V(typ)   V(min)   V(max)
0s        0V         0V         0V
470ps     -16mV      -2mV       -12mV
700ps     6mV        -17mV      769mV
920ps     441mV      -36mV      1.603V
1.14ns    987mV      120mV      2.07V
1.33ns    1.376V     369mV      2.264V
1.66ns    1.783V     842mV      2.349V
2.4ns     1.994V     1.489V     2.396V
3.39ns    2.035V     1.647V     2.411V
19.9ns    2.054V     1.7V       2.418V
[Falling Waveform]
R_fixture = 0.050k
V_fixture = 0.000
V_fixture_min = 0.000
V_fixture_max = 0.000
|   time   V(typ)   V(min)   V(max)
0s        2.054V     1.7V       2.418V
350ps     2.054V     1.702V     2.374V
450ps     2.022V     1.7V       2.117V
540ps     1.933V     1.689V     1.616V
810ps     1.087V     1.512V     237mV
1.06ns    279mV      1.006V     11mV
1.22ns    55mV       669mV      4mV
1.51ns    7mV        161mV      1mV
1.83ns    2mV        17mV       1mV
19.9ns    0V         0V         0V
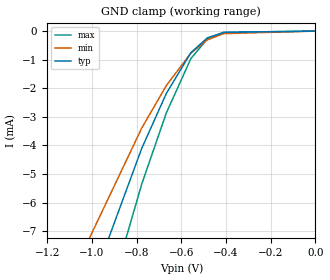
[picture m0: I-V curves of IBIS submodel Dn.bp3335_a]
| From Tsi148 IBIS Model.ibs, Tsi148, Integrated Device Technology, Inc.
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[Submodel]  Dn.bp3335_a
Submodel_type   Dynamic_clamp
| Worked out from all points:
|   GND clamp passes 1 mA (typ) near -0.58 V on its own axis
[GND Clamp]   | Note: Vtable =  Vout
| Voltage   I(typ)   I(min)   I(max)
-3.6V     -75.49mA   -59.88mA   -93.26mA
-1.437V   -18.93mA   -14.93mA   -24.01mA
-1.4V     -18.04mA   -14.23mA   -22.9mA
-1.253V   -14.52mA   -11.48mA   -18.51mA
-1.143V   -11.95mA   -9.479mA   -15.29mA
-1.107V   -11.11mA   -8.824mA   -14.23mA
-777mV    -4.102mA   -3.393mA   -5.353mA
-667mV    -2.182mA   -1.907mA   -2.862mA
-557mV    -752uA     -769uA     -960uA
-483mV    -234uA     -304uA     -267uA
-410mV    -47uA      -88uA      -43uA
0V        0A         0A         0A
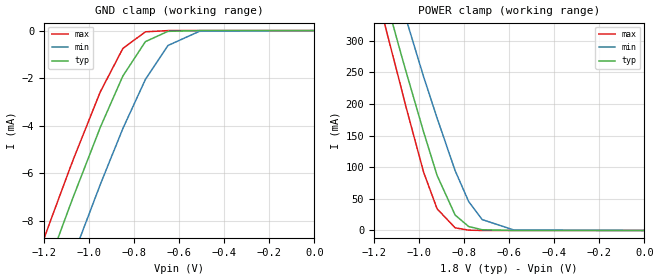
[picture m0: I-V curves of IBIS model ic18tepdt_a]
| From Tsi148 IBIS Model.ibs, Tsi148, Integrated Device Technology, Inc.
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|   MODEL ic18tepdt_a
[Model]   ic18tepdt_a
Model_type   Input
Vinl  = 0.63V
Vinh  = 1.17V
|   typ   min   max
C_comp   0.98pF   0.88pF  1.08pF
[Temperature Range]   50.00   125.00   0.00
[Voltage Range]   1.800   1.650   1.950
|   typ   min   max
|[Supply]   VDD   1.80   1.65   1.95
[Add Submodel]
| Submodel Name   Mode
Up.ic18tepdt_a   Non-Driving
Dn.ic18tepdt_a   Non-Driving
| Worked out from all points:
|   GND clamp passes 1 mA (typ) near -0.80 V on its own axis
|   POWER clamp passes 1 mA (typ) near -0.71 V on its own axis
[POWER_Clamp]   | Note: Vtable = Vcc - Vout
| Voltage   I(typ)   I(min)   I(max)
-1.95V    1.502A     1.515A     1.547A
-1.18V    409.4mA    486.3mA    365.4mA
-1.14V    356.3mA    435.8mA    308.7mA
-1.08V    278.9mA    361.4mA    226.2mA
-1.06V    253.8mA    337.1mA    197.9mA
-980mV    155.9mA    243.1mA    92.22mA
-920mV    86.96mA    177.7mA    34.21mA
-840mV    24.37mA    94.58mA    4.222mA
-780mV    6.248mA    45.82mA    508uA
-720mV    1.17mA     17.24mA    43uA
-580mV    9uA        802uA      0A
0V        0A         0A         0A
[GND_Clamp]   | Note: Vtable = Vout
| Voltage   I(typ)   I(min)   I(max)
-1.95V    -30.64mA   -33.06mA   -29.11mA
-1.25V    -11.66mA   -14.15mA   -10.07mA
-1.23V    -11.13mA   -13.62mA   -9.546mA
-1.17V    -9.565mA   -12.05mA   -7.977mA
-1.09V    -7.506mA   -9.985mA   -5.927mA
-1.07V    -7mA       -9.474mA   -5.425mA
-950mV    -4.069mA   -6.476mA   -2.576mA
-850mV    -1.912mA   -4.124mA   -751uA
-750mV    -465uA     -2.058mA   -52uA
-650mV    -32uA      -629uA     -1uA
-510mV    0A         -29uA      0A
0V        0A         0A         0A
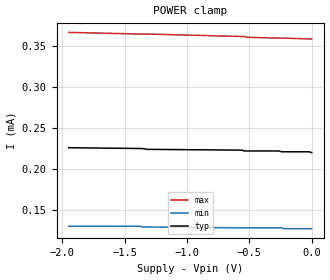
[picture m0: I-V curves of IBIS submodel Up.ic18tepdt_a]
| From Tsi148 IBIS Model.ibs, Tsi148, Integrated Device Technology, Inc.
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[Submodel]  Up.ic18tepdt_a
Submodel_type   Dynamic_clamp
[POWER Clamp]   | Note: Vtable = Vcc - Vout
| Voltage   I(typ)   I(min)   I(max)
-1.95V    226uA      130uA      367uA
-1.38V    225uA      130uA      365uA
-1.36V    225uA      129uA      365uA
-1.32V    224uA      129uA      365uA
-560mV    223uA      128uA      362uA
-540mV    222uA      128uA      362uA
-520mV    222uA      128uA      361uA
-260mV    222uA      128uA      360uA
-240mV    221uA      128uA      360uA
-220mV    221uA      127uA      360uA
-20mV     221uA      127uA      359uA
0V        220uA      127uA      359uA
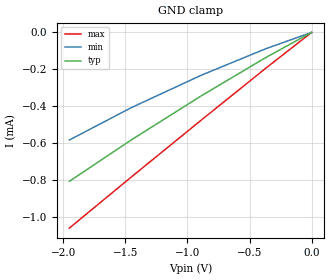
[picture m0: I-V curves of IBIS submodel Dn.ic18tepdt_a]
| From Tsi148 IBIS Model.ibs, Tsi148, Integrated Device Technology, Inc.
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[Submodel]  Dn.ic18tepdt_a
Submodel_type   Dynamic_clamp
[GND Clamp]   | Note: Vtable =  Vout
| Voltage   I(typ)   I(min)   I(max)
-1.95V    -808uA     -584uA     -1.062mA
-1.45V    -583uA     -408uA     -784uA
-890mV    -345uA     -233uA     -477uA
-370mV    -137uA     -89uA      -195uA
0V        0A         0A         0A
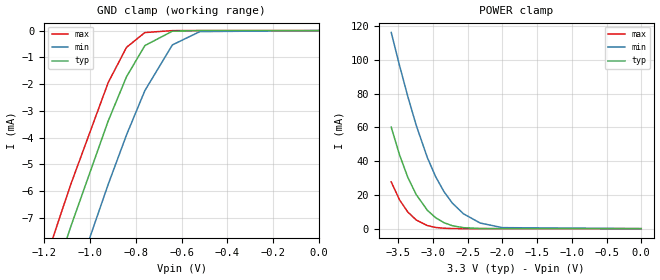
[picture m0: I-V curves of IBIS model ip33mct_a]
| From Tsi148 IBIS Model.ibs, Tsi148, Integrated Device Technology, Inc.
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|   MODEL ip33mct_a
[Model]   ip33mct_a
Model_type   Input
Vinl  = 0.8V
Vinh  = 2.0V
|   typ   min   max
C_comp   1.33pF   1.20pF  1.46pF
[Temperature Range]   50.00   125.00   0.00
[Voltage Range]   3.300   3.000   3.600
|   typ   min   max
|[Supply]   VDD   1.80   1.65   1.95
|[Supply]   VDD330   3.30   3.00   3.60
[Add Submodel]
| Submodel Name   Mode
Up.ip33mct_a   Non-Driving
Dn.ip33mct_a   Non-Driving
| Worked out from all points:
|   GND clamp passes 1 mA (typ) near -0.80 V on its own axis
|   POWER clamp passes 1 mA (typ) near -2.63 V on its own axis
[POWER_Clamp]   | Note: Vtable = Vcc - Vout
| Voltage   I(typ)   I(min)   I(max)
-3.6V     60.2mA     116.3mA    27.69mA
-3.48V    43.67mA    96.64mA    17.04mA
-3.36V    30.3mA     78.14mA    9.798mA
-3.24V    20.18mA    61.24mA    5.162mA
-3.08V    10.92mA    42.12mA    1.825mA
-2.96V    6.444mA    30.76mA    703uA
-2.84V    3.523mA    21.89mA    233uA
-2.72V    1.75mA     15.16mA    70uA
-2.56V    578uA      8.808mA    13uA
-2.32V    80uA       3.344mA    1uA
-2V       5uA        606uA      0A
0V        0A         0A         0A
[GND_Clamp]   | Note: Vtable = Vout
| Voltage   I(typ)   I(min)   I(max)
-3.6V     -76.49mA   -78.79mA   -75.06mA
-1.28V    -12.45mA   -14.94mA   -10.87mA
-1.24V    -11.4mA    -13.88mA   -9.809mA
-1.2V     -10.35mA   -12.84mA   -8.759mA
-1.12V    -8.273mA   -10.76mA   -6.689mA
-1.08V    -7.253mA   -9.729mA   -5.675mA
-920mV    -3.381mA   -5.752mA   -1.944mA
-840mV    -1.725mA   -3.901mA   -626uA
-760mV    -561uA     -2.244mA   -74uA
-640mV    -23uA      -536uA     -1uA
-520mV    0A         -38uA      0A
0V        0A         0A         0A
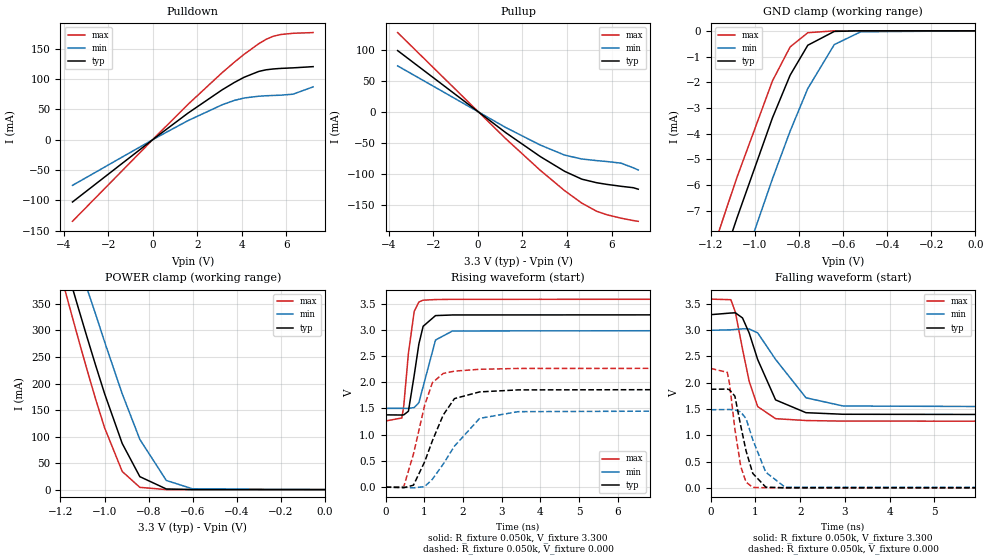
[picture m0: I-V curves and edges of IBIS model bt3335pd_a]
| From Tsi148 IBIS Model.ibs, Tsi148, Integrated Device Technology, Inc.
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|   MODEL bt3335pd_a
[Model]   bt3335pd_a
Model_type   I/O
Vinl  = 0.8V
Vinh  = 2.0V
Vref  = 0.0V
Rref  = 1k
Cref  = 10pF
Vmeas = 1.65V
| Values for delay from A to PAD (Tdo) are determined using
| Vref, Cref, Rref, and Vmeas.
|   INPUT TRANSITION ON DRIVER INPUT = 0.1ns
|   typ   min   max
| Tdo (rise)   1.65n   1.16n   2.35n
| Tdo (fall)   1.48n   1.10n   2.02n
|   INPUT TRANSITION ON DRIVER INPUT = 1.0ns
|   typ   min   max
| Tdo (rise)   1.86n   1.31n   2.61n
| Tdo (fall)   1.59n   1.21n   2.14n
|   typ   min   max
C_comp   6.07pF   6.06pF  6.08pF
[Temperature Range]   50.00   125.00   0.00
[Voltage Range]   3.300   3.000   3.600
|   typ   min   max
|[Supply]   VDD   1.80   1.65   1.95
|[Supply]   VDD330   3.30   3.00   3.60
[Add Submodel]
| Submodel Name   Mode
Up.bt3335pd_a   Non-Driving
Dn.bt3335pd_a   Non-Driving
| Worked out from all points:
|   slope of the pulldown table from 0 to 0.495 V, typ, clamps not added: 35.2 ohm
|   slope of the pullup table from 0 to 0.495 V, typ, clamps not added: 37 ohm
|   GND clamp passes 1 mA (typ) near -0.80 V on its own axis
|   POWER clamp passes 1 mA (typ) near -0.71 V on its own axis
|   rising waveform, R_fixture 0.050k, V_fixture 3.300: 20-80 % time 235ps typ, 287ps min, 190ps max; typ from 1.38 V to 3.29 V
|   falling waveform, R_fixture 0.050k, V_fixture 3.300: 20-80 % time 509ps typ, 714ps min, 358ps max; typ from 3.29 V to 1.38 V
|   rising waveform, R_fixture 0.050k, V_fixture 0.000: 20-80 % time 632ps typ, 858ps min, 450ps max; typ from 0 V to 1.87 V
|   falling waveform, R_fixture 0.050k, V_fixture 0.000: 20-80 % time 291ps typ, 389ps min, 215ps max; typ from 1.87 V to 0 V
[Pullup]   | Note: Vtable = Vcc - Vout
| Voltage   I(typ)   I(min)   I(max)
-3.6V     99.76mA    75.03mA    128.9mA
1.26V     -33.14mA   -24.78mA   -42.99mA
2.8V      -71.56mA   -52.93mA   -93.77mA
3.9V      -95.55mA   -69.32mA   -126.9mA
4.67V     -108.2mA   -75.57mA   -147mA
5.33V     -113.9mA   -78.12mA   -160mA
5.77V     -116.5mA   -79.56mA   -165.5mA
6.43V     -119.7mA   -82.31mA   -171.3mA
6.98V     -122mA     -89.82mA   -175.1mA
7.2V      -124.4mA   -93.3mA    -176.3mA
[Pulldown]   | Note: Vtable = Vout
| Voltage   I(typ)   I(min)   I(max)
-3.6V     -102.9mA   -75.44mA   -134.8mA
140mV     4.008mA    2.901mA    5.297mA
1.57V     43.57mA    31.24mA    57.89mA
3.11V     82.25mA    57.6mA     110.5mA
3.66V     94.45mA    64.86mA    127.9mA
4.1V      103.1mA    68.89mA    141mA
4.76V     112.8mA    71.84mA    158.6mA
5.09V     115.5mA    72.6mA     165.8mA
5.42V     116.9mA    73.14mA    171mA
5.75V     117.8mA    73.54mA    173.8mA
6.3V      118.7mA    75.22mA    175.8mA
7.2V      120.7mA    87.31mA    177mA
[POWER_Clamp]   | Note: Vtable = Vcc - Vout
| Voltage   I(typ)   I(min)   I(max)
-3.6V     3.946A     3.816A     4.188A
-1.2V     455.7mA    530.2mA    407.9mA
-1.16V    400.6mA    479.4mA    346.3mA
-1.12V    343.9mA    429.2mA    285.8mA
-1.08V    288.1mA    379.7mA    226.7mA
-1.04V    233.7mA    330.1mA    169.8mA
-1V       181.1mA    278.8mA    116.7mA
-920mV    86.97mA    180.7mA    34.22mA
-840mV    24.39mA    94.6mA     4.235mA
-720mV    1.176mA    17.25mA    44uA
-600mV    19uA       1.348mA    0A
0V        0A         0A         0A
[GND_Clamp]   | Note: Vtable = Vout
| Voltage   I(typ)   I(min)   I(max)
-3.6V     -76.49mA   -78.79mA   -75.06mA
-1.28V    -12.45mA   -14.94mA   -10.87mA
-1.24V    -11.4mA    -13.88mA   -9.809mA
-1.2V     -10.35mA   -12.84mA   -8.759mA
-1.12V    -8.273mA   -10.76mA   -6.689mA
-1.08V    -7.253mA   -9.729mA   -5.675mA
-920mV    -3.381mA   -5.752mA   -1.944mA
-840mV    -1.725mA   -3.901mA   -626uA
-760mV    -561uA     -2.244mA   -74uA
-640mV    -23uA      -536uA     -1uA
-520mV    0A         -38uA      0A
0V        0A         0A         0A
[Ramp]
| variable   typ   min   max
  dV/dt_r   1.12/0.63n   0.89/0.86n   1.36/0.45n
  dV/dt_f   1.15/0.51n   0.89/0.71n   1.39/0.36n
R_load = 0.050k
[Rising Waveform]
R_fixture = 0.050k
V_fixture = 3.300
V_fixture_min = 3.000
V_fixture_max = 3.600
|   time   V(typ)   V(min)   V(max)
0s        1.378V     1.502V     1.261V
420ps     1.375V     1.502V     1.319V
470ps     1.378V     1.501V     1.555V
590ps     1.448V     1.501V     2.556V
740ps     2.137V     1.518V     3.352V
860ps     2.729V     1.61V      3.531V
970ps     3.067V     1.918V     3.565V
1.29ns    3.271V     2.805V     3.577V
1.73ns    3.283V     2.978V     3.581V
19.9ns    3.29V      2.993V     3.585V
[Falling Waveform]
R_fixture = 0.050k
V_fixture = 3.300
V_fixture_min = 3.000
V_fixture_max = 3.600
|   time   V(typ)   V(min)   V(max)
0s        3.29V      2.993V     3.585V
450ps     3.321V     3.002V     3.574V
550ps     3.325V     3.009V     3.34V
710ps     3.228V     3.021V     2.639V
860ps     2.941V     3.018V     2.023V
1.05ns    2.437V     2.944V     1.544V
1.45ns    1.671V     2.44V      1.314V
2.13ns    1.428V     1.711V     1.279V
2.96ns    1.398V     1.555V     1.268V
19.9ns    1.378V     1.502V     1.261V
[Rising Waveform]
R_fixture = 0.050k
V_fixture = 0.000
V_fixture_min = 0.000
V_fixture_max = 0.000
|   time   V(typ)   V(min)   V(max)
0s        0V         0V         0V
470ps     -12mV      -1mV       10mV
720ps     37mV       -14mV      630mV
1.01ns    484mV      10mV       1.563V
1.21ns    886mV      151mV      1.992V
1.49ns    1.377V     441mV      2.168V
1.78ns    1.688V     782mV      2.212V
2.43ns    1.816V     1.311V     2.247V
3.42ns    1.854V     1.439V     2.263V
19.9ns    1.873V     1.484V     2.269V
[Falling Waveform]
R_fixture = 0.050k
V_fixture = 0.000
V_fixture_min = 0.000
V_fixture_max = 0.000
|   time   V(typ)   V(min)   V(max)
0s        1.873V     1.484V     2.269V
370ps     1.876V     1.488V     2.194V
420ps     1.863V     1.488V     1.982V
540ps     1.742V     1.48V      1.117V
670ps     1.183V     1.443V     410mV
790ps     702mV      1.315V     108mV
940ps     275mV      916mV      9mV
1.23ns    14mV       298mV      2mV
1.66ns    2mV        14mV       1mV
19.9ns    0V         0V         0V
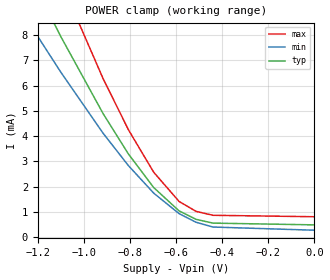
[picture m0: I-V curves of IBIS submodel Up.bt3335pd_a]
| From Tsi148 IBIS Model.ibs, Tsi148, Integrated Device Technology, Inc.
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[Submodel]  Up.bt3335pd_a
Submodel_type   Dynamic_clamp
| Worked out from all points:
|   POWER clamp passes 1 mA (typ) near -0.58 V on its own axis
[POWER Clamp]   | Note: Vtable = Vcc - Vout
| Voltage   I(typ)   I(min)   I(max)
-3.6V     59.91mA    47.21mA    75.46mA
-1.357V   12.65mA    10.24mA    16.06mA
-1.247V   10.58mA    8.615mA    13.45mA
-1.21V    9.908mA    8.083mA    12.6mA
-1.1V     7.937mA    6.528mA    10.12mA
-917mV    4.895mA    4.116mA    6.281mA
-807mV    3.292mA    2.832mA    4.253mA
-697mV    1.961mA    1.74mA     2.566mA
-587mV    1.037mA    929uA      1.411mA
-513mV    702uA      586uA      1.017mA
-440mV    553uA      398uA      863uA
0V        484uA      272uA      806uA
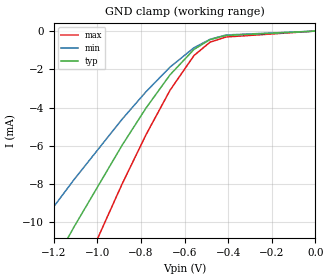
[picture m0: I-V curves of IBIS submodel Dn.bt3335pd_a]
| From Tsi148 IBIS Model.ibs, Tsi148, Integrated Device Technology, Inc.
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[Submodel]  Dn.bt3335pd_a
Submodel_type   Dynamic_clamp
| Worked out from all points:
|   GND clamp passes 1 mA (typ) near -0.56 V on its own axis
[GND Clamp]   | Note: Vtable =  Vout
| Voltage   I(typ)   I(min)   I(max)
-3.6V     -66.58mA   -50.05mA   -85.74mA
-1.51V    -18.68mA   -14.04mA   -24.57mA
-1.29V    -14mA      -10.56mA   -18.5mA
-1.143V   -10.98mA   -8.315mA   -14.56mA
-1.107V   -10.24mA   -7.766mA   -13.59mA
-887mV    -5.977mA   -4.614mA   -8.005mA
-777mV    -4.024mA   -3.171mA   -5.42mA
-667mV    -2.289mA   -1.885mA   -3.095mA
-557mV    -958uA     -869uA     -1.278mA
-483mV    -442uA     -429uA     -577uA
-410mV    -229uA     -203uA     -309uA
0V        0A         0A         0A
